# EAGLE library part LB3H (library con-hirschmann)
Female RF CONNECTOR with switch, horizontal

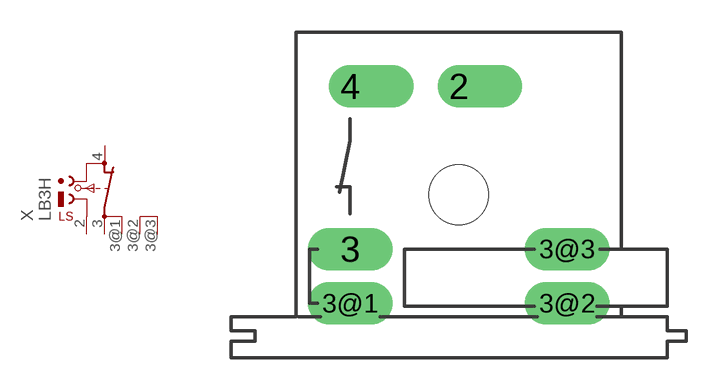
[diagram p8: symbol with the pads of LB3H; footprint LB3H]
Designator prefix X

## LB3H  [LB3H]
2  2  pas
3  3  pas
3@1  3A  pas
3@2  3B  pas
3@3  3C  pas
4  4  pas

## Footprint LB3H (pad centres in mm)
Female RF CONNECTOR with switch horizontal
drill 1.321 offset: 2 0,5.08; 4 -5.08,5.08
drill 1.321 long: 3 -5.08,-2.54; 3@1 -5.08,-5.08; 3@2 5.08,-5.08; 3@3 5.08,-2.54
hole 2.794 at 0,0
